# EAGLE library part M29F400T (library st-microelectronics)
FLASH MEMORY 512 KB x 8 or 256 KB x 16, boot block

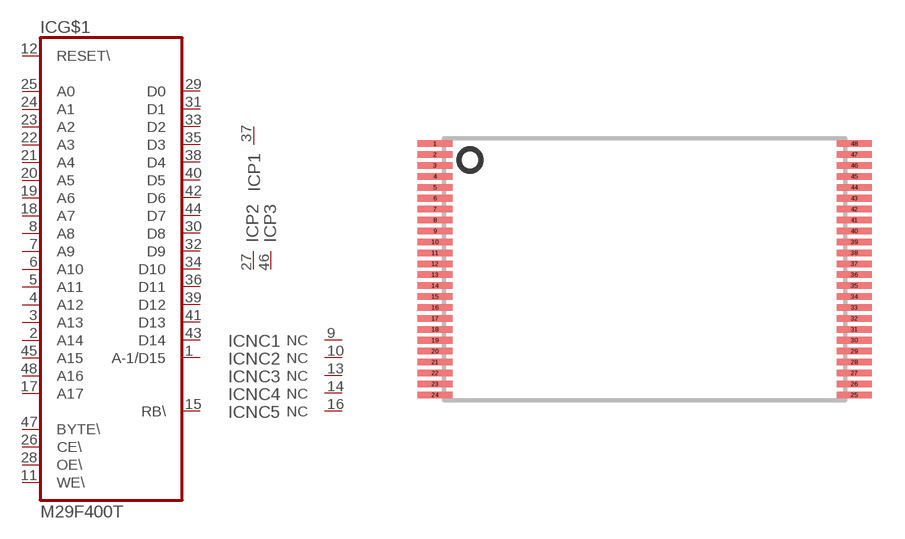
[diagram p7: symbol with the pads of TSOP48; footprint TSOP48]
Designator prefix IC; gates G$1=M29F400 P1=VCC P2=GND P3=GND NC1=NC NC2=NC NC3=NC NC4=NC NC5=NC

## M29F400T  [TSOP48]
1  G$1:A-1/D15  hiz
2  G$1:A14  in
3  G$1:A13  in
4  G$1:A12  in
5  G$1:A11  in
6  G$1:A10  in
7  G$1:A9  in
8  G$1:A8  in
9  NC1:NC  nc
10  NC2:NC  nc
11  G$1:WE\  in
12  G$1:RESET\  in
13  NC3:NC  nc
14  NC4:NC  nc
15  G$1:RB\  out
16  NC5:NC  nc
17  G$1:A17  in
18  G$1:A7  in
19  G$1:A6  in
20  G$1:A5  in
21  G$1:A4  in
22  G$1:A3  in
23  G$1:A2  in
24  G$1:A1  in
25  G$1:A0  in
26  G$1:CE\  in
27  P2:GND  pwr
28  G$1:OE\  in
29  G$1:D0  hiz
30  G$1:D8  hiz
31  G$1:D1  hiz
32  G$1:D9  hiz
33  G$1:D2  hiz
34  G$1:D10  hiz
35  G$1:D3  hiz
36  G$1:D11  hiz
37  P1:VCC  pwr
38  G$1:D4  hiz
39  G$1:D12  hiz
40  G$1:D5  hiz
41  G$1:D13  hiz
42  G$1:D6  hiz
43  G$1:D14  hiz
44  G$1:D7  hiz
45  G$1:A15  in
46  P3:GND  pwr
47  G$1:BYTE\  in
48  G$1:A16  in

## Footprint TSOP48 (pad centres in mm)
Thin Small Outline Package
smd 1.6 x 0.3: 1 -9.6,5.75; 2 -9.6,5.25; 3 -9.6,4.75; 4 -9.6,4.25; 5 -9.6,3.75; 6 -9.6,3.25; 7 -9.6,2.75; 8 -9.6,2.25; 9 -9.6,1.75; 10 -9.6,1.25; 11 -9.6,0.75; 12 -9.6,0.25; 13 -9.6,-0.25; 14 -9.6,-0.75; 15 -9.6,-1.25; 16 -9.6,-1.75; 17 -9.6,-2.25; 18 -9.6,-2.75; 19 -9.6,-3.25; 20 -9.6,-3.75; 21 -9.6,-4.25; 22 -9.6,-4.75; 23 -9.6,-5.25; 24 -9.6,-5.75; 25 9.6,-5.75; 26 9.6,-5.25; 27 9.6,-4.75; 28 9.6,-4.25; 29 9.6,-3.75; 30 9.6,-3.25; 31 9.6,-2.75; 32 9.6,-2.25; 33 9.6,-1.75; 34 9.6,-1.25; 35 9.6,-0.75; 36 9.6,-0.25; 37 9.6,0.25; 38 9.6,0.75; 39 9.6,1.25; 40 9.6,1.75; 41 9.6,2.25; 42 9.6,2.75; 43 9.6,3.25; 44 9.6,3.75; 45 9.6,4.25; 46 9.6,4.75; 47 9.6,5.25; 48 9.6,5.75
